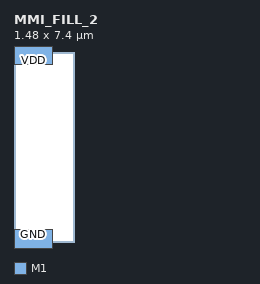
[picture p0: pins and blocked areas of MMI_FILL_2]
MACRO MMI_FILL_2
	CLASS CORE ;
	FOREIGN MMI_FILL_2 0 0 ;
	SIZE 1.48 BY 7.4 ;
	SYMMETRY X Y ;
	SITE CORE1 ;
	PIN GND
		DIRECTION inout ;
		USE GROUND ;
		PORT
			LAYER M1 ;
			RECT 0 -0.5 1.48 0.5 ;
		END
	END GND
	PIN VDD
		DIRECTION inout ;
		USE POWER ;
		PORT
			LAYER M1 ;
			RECT 0 6.9 1.48 7.9 ;
		END
	END VDD
	OBS
	END
END MMI_FILL_2
